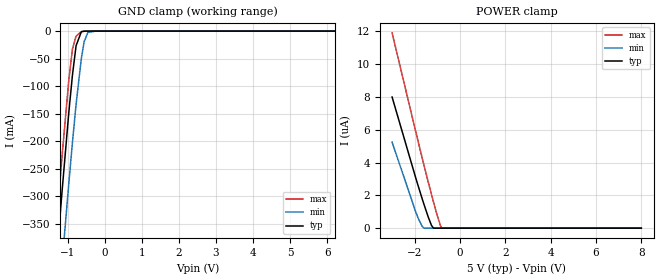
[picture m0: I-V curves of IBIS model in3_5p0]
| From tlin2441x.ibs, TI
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|   in3_5p0 Model
[Model]   in3_5p0
Model_type   Input
Vinl = 0.8
Vinh = 2
|   typ   min   max
C_comp   4.243pF   3.996pF   4.243pF
|  Where Nom  PVT is Nominal Process, 5.0V,   27C
|   Fast PVT is Strong Process,  5.5,   -40C
|   Slow PVT is Weak Process,   4.5V,   150C
[Voltage Range]   5   4.5   5.5
|Junction Temperature
[Temperature Range]   27   150   -40
[Power Clamp Reference]   5   4.5   5.5
[GND Clamp Reference]   0   0   0
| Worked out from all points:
|   GND clamp passes 1 mA (typ) near -0.63 V on its own axis
[GND Clamp]
|   Voltage   I(typ)   I(min)   I(max)
-3V       -1.934A    -2.032A    -1.89A
-1.537V   -616.5mA   -743.5mA   -555.5mA
-1.196V   -324mA     -455.1mA   -260.2mA
-1.152V   -287.7mA   -418.9mA   -223.9mA
-976mV    -149.3mA   -278.1mA   -90.15mA
-877mV    -80.52mA   -203.1mA   -32.85mA
-778mV    -26.6mA    -133.2mA   -9.143mA
-635mV    -1.049mA   -49.26mA   -1.125mA
-558mV    -166.2uA   -18.82mA   -193.4uA
-459mV    -24.47uA   -2.442mA   -25.18uA
-239mV    -12.7uA    -19.14uA   -14.71uA
8V        0A         0A         0A
[POWER Clamp]
|   Voltage   I(typ)   I(min)   I(max)
-3V       7.991uA    5.243uA    11.9uA
-1.955V   3.056uA    983.8nA    5.872uA
-1.834V   2.508uA    561.3nA    5.188uA
-1.669V   1.778uA    101.8nA    4.261uA
-1.581V   1.401uA    0A         3.771uA
-1.405V   679nA      0A         2.813uA
-1.262V   169.8nA    0A         2.059uA
-1.174V   0A         0A         1.602uA
-1.02V    0A         0A         826.8nA
-855mV    0A         0A         113.1nA
-811mV    0A         0A         6.303nA
8V        0A         0A         0A
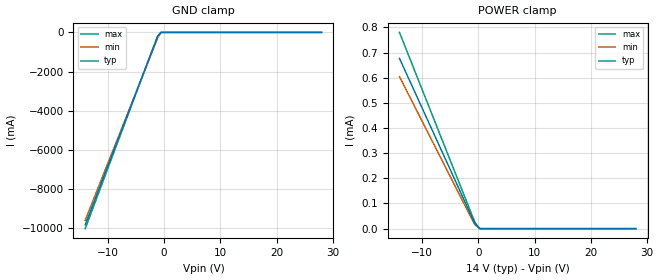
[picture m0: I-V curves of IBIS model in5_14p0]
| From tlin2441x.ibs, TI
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|   in5_14p0 Model
[Model]   in5_14p0
Model_type   Input
Vinl = 11
Vinh = 12
|   typ   min   max
C_comp   5.416pF   5.292pF   5.491pF
|  Where Nom  PVT is Nominal Process, 14.0V,   27C
|   Fast PVT is Strong Process,  16.0,   -40C
|   Slow PVT is Weak Process,   12.0V,   150C
[Model spec]
|subparameter
Vinl   11   9   13
Vinh   12   10   14
[Voltage Range]   14   12   16
|Junction Temperature
[Temperature Range]   27   150   -40
[Power Clamp Reference]   14   12   16
[GND Clamp Reference]   0   0   0
[GND Clamp]
|   Voltage   I(typ)   I(min)   I(max)
-14V      -9.81A     -9.582A    -10.01A
-1.148V   -225.2mA   -296.1mA   -196.2mA
-560mV    -10.69uA   -3.202mA   -8.464uA
238mV     -1.926uA   -161.2uA   -2.474uA
322mV     -1.458uA   -1.139uA   -2.151uA
28V       0A         0A         0A
[POWER Clamp]
|   Voltage   I(typ)   I(min)   I(max)
-14V      676.6uA    604.2uA    779.9uA
-1.148V   46.93uA    38.58uA    55.81uA
-560mV    19.26uA    14.6uA     23.85uA
238mV     897.5nA    673.4nA    1.118uA
322mV     0A         0A         0A
28V       0A         0A         0A
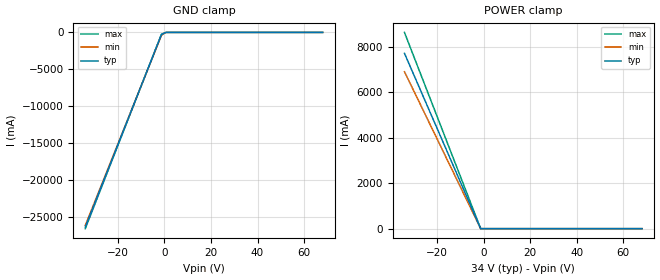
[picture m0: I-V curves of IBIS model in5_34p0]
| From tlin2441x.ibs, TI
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|   in5_34p0 Model
[Model]   in5_34p0
Model_type   Input
Vinl = 31
Vinh = 32
|   typ   min   max
C_comp   3.834pF   3.781pF   3.834pF
|  Where Nom  PVT is Nominal Process, 34.0V,   27C
|   Fast PVT is Strong Process,  36.0,   -40C
|   Slow PVT is Weak Process,   32.0V,   150C
[Model spec]
|subparameter
Vinl   31   29   33
Vinh   32   30   34
[Voltage Range]   34   32   36
[Temperature Range]   27   150   -40
[Power Clamp Reference]   34   32   36
[GND Clamp Reference]   0   0   0
[GND Clamp]
|   Voltage   I(typ)   I(min)   I(max)
-34V      -26.35A    -26.11A    -26.55A
-1.258V   -283.2mA   -377.4mA   -244mA
-238mV    -134.2mA   -178.8mA   -115.6mA
578mV     -14.91mA   -19.87mA   -12.85mA
782mV     -4.405uA   -3.704uA   -5.883uA
68V       0A         0A         0A
[POWER Clamp]
|   Voltage   I(typ)   I(min)   I(max)
-34V      7.726A     6.916A     8.648A
-1.258V   55.12uA    46.31uA    64.83uA
-238mV    26.03uA    21.85uA    30.62uA
578mV     2.746uA    2.289uA    3.247uA
782mV     0A         0A         0A
68V       0A         0A         0A
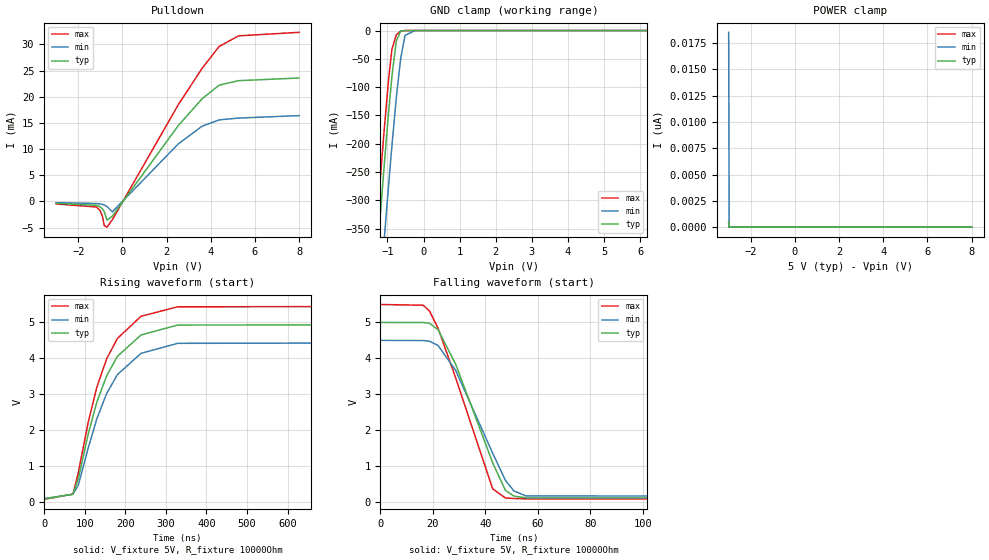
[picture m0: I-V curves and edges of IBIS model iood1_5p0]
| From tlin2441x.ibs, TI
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|   iood1_5p0 Model
[Model]   iood1_5p0
Model_type   I/O_open_drain
Polarity   Non-Inverting
Enable   Active-Low
Vinl = 0.8
Vinh = 2
Vmeas = 2.5
Vref = 5
Cref = 2pF
Rref = 10000
|   typ   min   max
C_comp   4.504pF   4.262pF   4.504pF
|  Where Nom  PVT is Nominal Process, 5.0V,   27C
|   Fast PVT is Strong Process,  5.5,   -40C
|   Slow PVT is Weak Process,   4.5V,   150C
[Voltage Range]   5   4.5   5.5
|Junction Temperature
[Temperature Range]   27   150   -40
[Pullup Reference]   5   4.5   5.5
[Pulldown Reference]   0   0   0
[Power Clamp Reference]   5   4.5   5.5
[GND Clamp Reference]   0   0   0
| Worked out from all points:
|   slope of the pulldown table from 0 to 0.75 V, typ, clamps not added: 165 ohm
|   GND clamp passes 1 mA (typ) near -0.63 V on its own axis
|   falling waveform, V_fixture 5V, R_fixture 10000Ohm: 20-80 % time 15.3ns typ, 16.1ns min, 14.6ns max; typ from 5 V to 0.08 V
|   rising waveform, V_fixture 5V, R_fixture 10000Ohm: 20-80 % time 85.8ns typ, 89ns min, 83.2ns max; typ from 0.08 V to 5 V
[Pulldown]
|   Voltage   I(typ)   I(min)   I(max)
-3V       -362.7uA   -227.6uA   -475.8uA
-1.185V   -734.4uA   -383.9uA   -1.054mA
-1.009V   -1.022mA   -473uA     -1.717mA
-899mV    -1.428mA   -567.9uA   -2.915mA
-822mV    -1.969mA   -670.4uA   -4.619mA
-701mV    -3.562mA   -943.5uA   -4.905mA
-459mV    -2.81mA    -1.979mA   -3.509mA
2.533V    14.51mA    11mA       18.49mA
3.611V    19.62mA    14.38mA    25.43mA
4.381V    22.21mA    15.57mA    29.59mA
5.261V    23.06mA    15.92mA    31.62mA
8V        23.57mA    16.39mA    32.29mA
[GND Clamp]
|   Voltage   I(typ)   I(min)   I(max)
-3V       -1.935A    -2.032A    -1.89A
-1.537V   -616.6mA   -743.7mA   -555.7mA
-1.207V   -333.3mA   -464.4mA   -269.5mA
-1.141V   -278.9mA   -410.2mA   -215.2mA
-1.086V   -234.5mA   -365.5mA   -171.4mA
-965mV    -141.4mA   -269.8mA   -83.06mA
-877mV    -80.75mA   -203.3mA   -33.19mA
-756mV    -18.43mA   -119mA     -7.406mA
-635mV    -1.092mA   -49.56mA   -1.17mA
-514mV    -52.22uA   -8.686mA   -55.92uA
-239mV    0A         -7.41uA    0A
8V        0A         0A         0A
[POWER Clamp]
|   Voltage   I(typ)   I(min)   I(max)
-3V       445.5pA    18.51nA    459.1pA
-2.978V   0A         0A         0A
-2.967V   0A         0A         0A
8V        0A         0A         0A
[Ramp]
R_load = 10000
|   typ   min   max
dV/dt_r   2.9519/8.54854e-08   2.6451/8.86345e-08   3.25753/8.27986e-08
dV/dt_f   2.9519/1.52343e-08   2.6451/1.60653e-08   3.25753/1.46163e-08
[Falling Waveform]
V_fixture = 5V
V_fixture_min = 4.5V
V_fixture_max = 5.5V
R_fixture = 10000Ohm
C_fixture = 0F
|   Time   V(typ)   V(min)   V(max)
0s        5V         4.5V       5.5V
16.33ns   4.998V     4.496V     5.48V
18.68ns   4.978V     4.479V     5.323V
22ns      4.797V     4.358V     4.838V
28.7ns    3.835V     3.663V     3.455V
42.81ns   1.083V     1.35V      362.2mV
47.62ns   320.3mV    600mV      108.5mV
50.85ns   161.9mV    305.4mV    93.44mV
55.48ns   111mV      164.9mV    85.05mV
5us       80.16mV    91.37mV    70.78mV
[Rising Waveform]
V_fixture = 5V
V_fixture_min = 4.5V
V_fixture_max = 5.5V
R_fixture = 10000Ohm
C_fixture = 0F
|   Time   V(typ)   V(min)   V(max)
0s        80.16mV    91.37mV    70.78mV
71.29ns   214.9mV    213.3mV    215.2mV
84.38ns   644.2mV    465.9mV    818.2mV
109ns     1.899V     1.509V     2.229V
130ns     2.778V     2.316V     3.196V
154.4ns   3.518V     3.024V     3.991V
180.8ns   4.056V     3.548V     4.556V
238.8ns   4.651V     4.139V     5.171V
329ns     4.927V     4.418V     5.436V
5us       5V         4.5V       5.5V
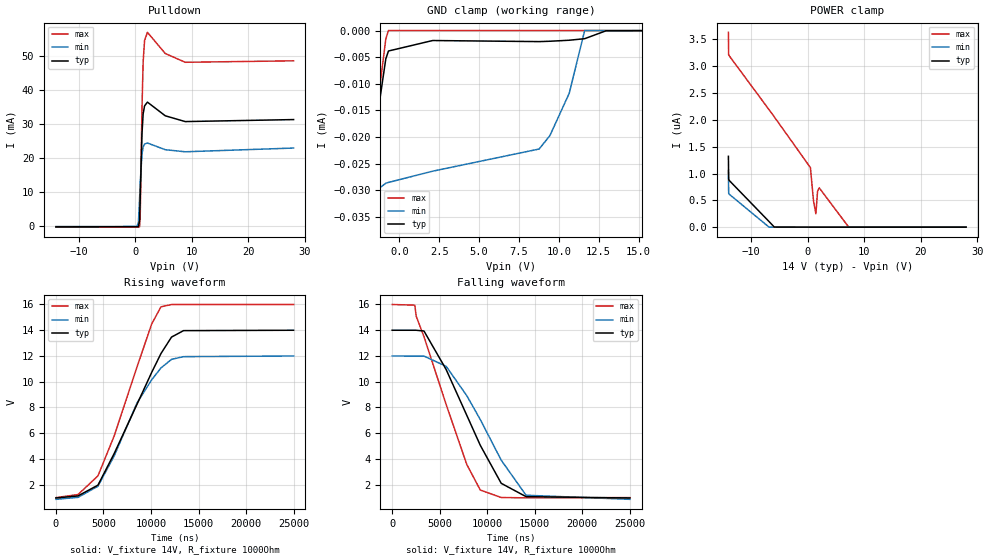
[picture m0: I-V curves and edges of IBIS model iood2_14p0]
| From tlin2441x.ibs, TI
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|   iood2_14p0 Model
[Model]   iood2_14p0
Model_type   I/O_open_drain
Polarity   Non-Inverting
Enable   Active-Low
Vinl = 2.8
Vinh = 11.9
Vmeas = 7
Vref = 14
Cref = 2pF
Rref = 1000
|   typ   min   max
C_comp   6.786pF   6.632pF   7.441pF
|  Where Nom  PVT is Nominal Process, 14.0V,   27C
|   Fast PVT is Strong Process,  16.0,   -40C
|   Slow PVT is Weak Process,   12.0V,   150C
[Model spec]
|subparameter
Vinl   2.8   2.4   3.2
Vinh   11.9   10.2   13.6
[Voltage Range]   14   12   16
|Junction Temperature
[Temperature Range]   27   150   -40
[Pullup Reference]   14   12   16
[Pulldown Reference]   0   -0   -0
[Power Clamp Reference]   14   12   16
[GND Clamp Reference]   0   0   0
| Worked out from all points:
|   slope of the pulldown table from 0 to 2.1 V, typ, clamps not added: 57.3 ohm
|   falling waveform, V_fixture 14V, R_fixture 1000Ohm: 20-80 % time 4.85us typ, 4.91us min, 4.05us max; typ from 14 V to 0.969 V
|   rising waveform, V_fixture 14V, R_fixture 1000Ohm: 20-80 % time 4.86us typ, 4.31us min, 4.14us max; typ from 0.969 V to 14 V
[Pulldown]
|   Voltage   I(typ)   I(min)   I(max)
-14V      -300.5uA   -219.8uA   -400.2uA
280mV     -279.7uA   -183.1uA   -374.2uA
574mV     -270.7uA   786.7uA    -366.6uA
784mV     1.521mA    8.053mA    -303.7uA
910mV     9.268mA    13.07mA    4.138mA
1.204V    26.99mA    21.05mA    34.35mA
1.414V    33.01mA    23.23mA    48.29mA
1.666V    35.35mA    24.1mA     54.65mA
2.17V     36.45mA    24.41mA    57.03mA
5.32V     32.43mA    22.43mA    50.79mA
8.848V    30.72mA    21.82mA    48.2mA
28V       31.31mA    22.92mA    48.63mA
[GND Clamp]
|   Voltage   I(typ)   I(min)   I(max)
-14V      -297.2uA   -267.5uA   -336.2uA
-2.324V   -36.2uA    -37.33uA   -37.54uA
-1.736V   -23.33uA   -30.73uA   -22.73uA
-854mV    -5.32uA    -28.65uA   -1.576uA
-686mV    -3.845uA   -28.51uA   0A
2.086V    -1.877uA   -26.4uA    0A
8.764V    -2.081uA   -22.24uA   0A
9.436V    -2.014uA   -19.74uA   0A
10.65V    -1.824uA   -11.8uA    0A
11.62V    -1.534uA   0A         0A
12.96V    -50.39nA   0A         0A
28V       0A         0A         0A
[POWER Clamp]
|   Voltage   I(typ)   I(min)   I(max)
-14V      1.321uA    1.061uA    3.633uA
-13.96V   891.5nA    635nA      3.217uA
-13.79V   863.5nA    608.2nA    3.186uA
-6.818V   104.6nA    120.1pA    2.19uA
-5.894V   1.97nA     0A         2.057uA
490mV     0A         0A         1.11uA
1.036V    0A         0A         489.3nA
1.456V    0A         0A         249.6nA
1.75V     0A         0A         668.6nA
2.044V    0A         0A         733.5nA
7.252V    0A         0A         1.455nA
28V       0A         0A         0A
[Ramp]
R_load = 1000
|   typ   min   max
dV/dt_r   7.8177/4.84794e-06   6.67991/4.29211e-06   8.99927/4.1215e-06
dV/dt_f   7.8177/4.85367e-06   6.67991/4.8993e-06   8.99927/4.04204e-06
[Falling Waveform]
V_fixture = 14V
V_fixture_min = 12V
V_fixture_max = 16V
R_fixture = 1000Ohm
C_fixture = 0F
|   Time   V(typ)   V(min)   V(max)
0s        14V        12V        16V
2.38us    14V        11.99V     15.95V
2.528us   14V        11.99V     15.09V
3.347us   13.94V     11.99V     13.5V
5.677us   10.95V     11.2V      8.239V
7.85us    7.39V      8.916V     3.572V
9.267us   5.066V     7.064V     1.59V
11.47us   2.11V      3.909V     1.007V
14.08us   1.075V     1.185V     981.8mV
25us      969.3mV    866.6mV    999.4mV
[Rising Waveform]
V_fixture = 14V
V_fixture_min = 12V
V_fixture_max = 16V
R_fixture = 1000Ohm
C_fixture = 0F
|   Time   V(typ)   V(min)   V(max)
0s        969.3mV    866.6mV    999.4mV
2.324us   1.132V     1.021V     1.237V
4.421us   1.968V     1.885V     2.687V
6.121us   4.41V      4.228V     5.775V
8.544us   8.271V     8.37V      11.18V
10.07us   10.72V     10.15V     14.48V
11.05us   12.19V     11.07V     15.82V
12.16us   13.47V     11.74V     16V
13.42us   13.97V     11.95V     16V
25us      14V        12V        16V
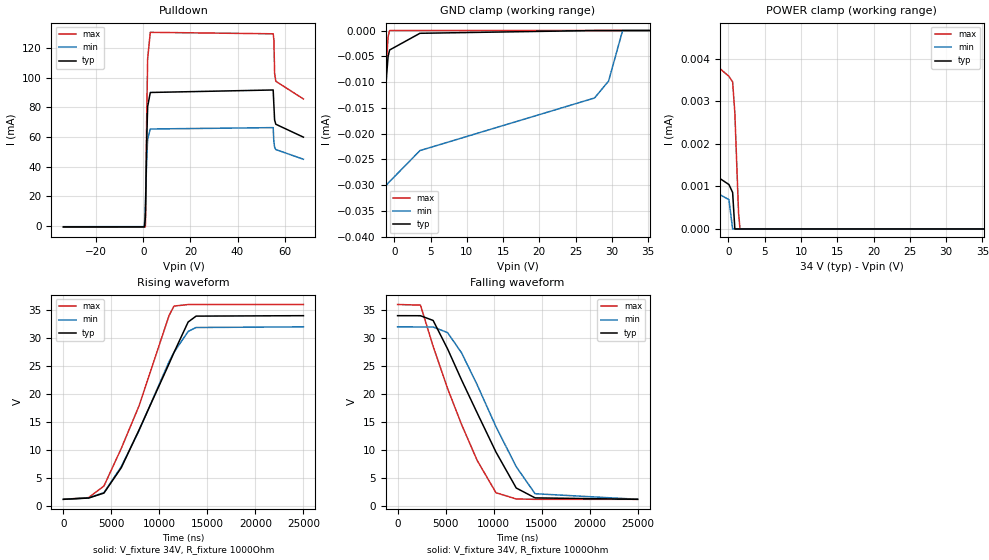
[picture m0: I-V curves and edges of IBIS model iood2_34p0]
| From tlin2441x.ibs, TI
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|   iood2_34p0 Model
[Model]   iood2_34p0
Model_type   I/O_open_drain
Polarity   Non-Inverting
Enable   Active-Low
Vinl = 6.8
Vinh = 28.9
Vmeas = 17
Vref = 34
Cref = 2pF
Rref = 1000
|   typ   min   max
C_comp   5.803pF   5.723pF   6.161pF
|  Where Nom  PVT is Nominal Process, 34.0V,   27C
|   Fast PVT is Strong Process,  36.0,   -40C
|   Slow PVT is Weak Process,   32.0V,   150C
[Model spec]
|subparameter
Vinl   6.8   6.4   7.2
Vinh   28.9   27.2   30.6
[Voltage Range]   34   32   36
|Junction Temperature
[Temperature Range]   27   150   -40
[Pullup Reference]   34   32   36
[Pulldown Reference]   0   -0   -0
[Power Clamp Reference]   34   32   36
[GND Clamp Reference]   0   0   0
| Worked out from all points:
|   slope of the pulldown table from 0 to 5.1 V, typ, clamps not added: 56.8 ohm
|   POWER clamp passes 1 mA (typ) near -21.23 V on its own axis
|   falling waveform, V_fixture 34V, R_fixture 1000Ohm: 20-80 % time 5.43us typ, 5.09us min, 4.67us max; typ from 34 V to 1.12 V
|   rising waveform, V_fixture 34V, R_fixture 1000Ohm: 20-80 % time 5.23us typ, 4.89us min, 4.65us max; typ from 1.12 V to 34 V
[Pulldown]
|   Voltage   I(typ)   I(min)   I(max)
-34V      -731.9uA   -590.3uA   -901.2uA
374mV     -715.2uA   -552.4uA   -876.9uA
782mV     4.155mA    10.28mA    -811.9uA
884mV     8.931mA    16.62mA    1.897mA
1.394V    57.12mA    44.58mA    72.35mA
1.802V    80.53mA    58.57mA    112.9mA
2.924V    90.07mA    65.4mA     130.7mA
55.15V    91.76mA    66.33mA    129.7mA
55.45V    81.51mA    56.53mA    125.7mA
55.76V    71.46mA    53.19mA    103.1mA
56.27V    68.61mA    51.51mA    97.64mA
68V       59.89mA    44.96mA    85.69mA
[GND Clamp]
|   Voltage   I(typ)   I(min)   I(max)
-34V      -746.5uA   -667uA     -852.3uA
-2.482V   -39.43uA   -39.89uA   -41.28uA
-2.38V    -37.18uA   -38.11uA   -38.7uA
-1.972V   -28.21uA   -32.86uA   -28.39uA
-1.054V   -8.644uA   -29.94uA   -5.684uA
-850mV    -5.027uA   -29.61uA   -1.204uA
-646mV    -3.779uA   -29.31uA   0A
3.536V    -537.8nA   -23.29uA   0A
27.61V    0A         -13.09uA   0A
29.55V    0A         -9.798uA   0A
31.48V    0A         0A         0A
68V       0A         0A         0A
[POWER Clamp]
|   Voltage   I(typ)   I(min)   I(max)
-34V      3.941A     3.346A     4.578A
-21.05V   32.09uA    64.38uA    375.6mA
-20.23V   3.232uA    7.134uA    167.3mA
-19.62V   3.168uA    2.974uA    26.5mA
-19.21V   3.127uA    2.522uA    117.3uA
-8.398V   2.001uA    1.48uA     4.82uA
68mV      1.044uA    688.9nA    3.587uA
578mV     857.8nA    0A         3.457uA
884mV     0A         0A         2.724uA
1.394V    0A         0A         376.6nA
1.598V    0A         0A         0A
68V       0A         0A         0A
[Ramp]
R_load = 1000
|   typ   min   max
dV/dt_r   19.7248/5.22925e-06   18.5236/4.88249e-06   20.9252/4.65492e-06
dV/dt_f   19.7248/5.43378e-06   18.5236/5.08419e-06   20.9252/4.67566e-06
[Falling Waveform]
V_fixture = 34V
V_fixture_min = 32V
V_fixture_max = 36V
R_fixture = 1000Ohm
C_fixture = 0F
|   Time   V(typ)   V(min)   V(max)
0s        34V        32V        36V
2.383us   33.99V     31.98V     35.89V
3.705us   33.14V     31.97V     28.51V
5.205us   28.07V     30.97V     20.98V
6.658us   22.52V     27.37V     14.55V
8.296us   16.57V     21.61V     8.071V
10.25us   9.579V     14.12V     2.302V
12.36us   3.146V     6.963V     1.184V
14.32us   1.381V     2.126V     1.121V
25us      1.122V     1.126V     1.12V
[Rising Waveform]
V_fixture = 34V
V_fixture_min = 32V
V_fixture_max = 36V
R_fixture = 1000Ohm
C_fixture = 0F
|   Time   V(typ)   V(min)   V(max)
0s        1.122V     1.126V     1.12V
2.623us   1.351V     1.373V     1.426V
4.222us   2.24V      2.32V      3.501V
6.028us   6.78V      6.962V     10.24V
7.88us    13.55V     13.43V     17.86V
11us      25.37V     25.74V     34V
11.52us   27.42V     27.44V     35.72V
12.99us   32.86V     31.17V     35.99V
13.82us   33.92V     31.88V     35.99V
25us      34V        32V        36V
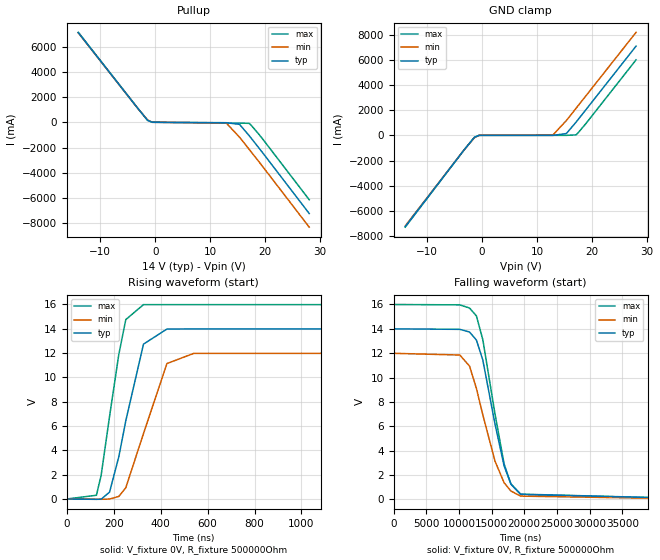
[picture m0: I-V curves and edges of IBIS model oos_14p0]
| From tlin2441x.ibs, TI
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|   oos_14p0 Model
[Model]   oos_14p0
Model_type   Open_source
Polarity   Non-Inverting
Vmeas = 7
Vref = 0
Cref = 2pF
Rref = 500000
|   typ   min   max
C_comp   1.013pF   0.976pF   1.013pF
|  Where Nom  PVT is Nominal Process, 14.0V,   27C
|   Fast PVT is Strong Process,  16.0,   -40C
|   Slow PVT is Weak Process,   12.0V,   150C
[Voltage Range]   14   12   16
|Junction Temperature
[Temperature Range]   27   150   -40
[Pullup Reference]   14   12   16
[Pulldown Reference]   0   0   0
[Power Clamp Reference]   14   12   16
[GND Clamp Reference]   0   0   0
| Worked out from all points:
|   slope of the pullup table from 0 to 2.1 V, typ, clamps not added: 142 ohm
|   falling waveform, V_fixture 0V, R_fixture 500000Ohm: 20-80 % time 3.14us typ, 3.55us min, 3.03us max; typ from 14 V to 0 V
|   rising waveform, V_fixture 0V, R_fixture 500000Ohm: 20-80 % time 89.4ns typ, 110ns min, 73.5ns max; typ from 0 V to 14 V
[GND Clamp]
|   Voltage   I(typ)   I(min)   I(max)
-14V      -7.247A    -7.195A    -7.29A
-3.5V     -1.275A    -1.274A    -1.28A
-3.08V    -1.045A    -1.045A    -1.048A
-1.4V     -157.1mA   -187mA     -145.4mA
-560mV    -1.434uA   -250.3uA   -1.025uA
12.88V    1.327nA    33.61mA    1.167nA
15.32V    142.8mA    1.178A     1.63nA
17.08V    1.048A     2.147A     37.06mA
17.5V     1.279A     2.379A     226.5mA
18.89V    2.045A     3.145A     944.9mA
19.6V     2.44A      3.541A     1.339A
28V       7.089A     8.181A     5.998A
[Pullup]
|   Voltage   I(typ)   I(min)   I(max)
-14V      7.117A     7.096A     7.143A
-3.5V     1.285A     1.281A     1.294A
-3.08V    1.053A     1.051A     1.061A
-1.4V     163.7mA    191.7mA    154.9mA
-560mV    4.279mA    2.278mA    7.702mA
12.88V    -30.79mA   -40.71mA   -59.53mA
15.32V    -161.6mA   -1.179A    -59.53mA
17.08V    -1.059A    -2.145A    -80.65mA
17.5V     -1.289A    -2.377A    -261.2mA
18.8V     -2.007A    -3.097A    -922.5mA
19.6V     -2.454A    -3.547A    -1.362A
28V       -7.237A    -8.32A     -6.141A
[Ramp]
R_load = 500000
|   typ   min   max
dV/dt_r   8.39773/8.94312e-08   7.19586/1.10056e-07   9.59854/7.35254e-08
dV/dt_f   8.39773/3.13035e-06   7.19586/3.55426e-06   9.59854/3.02909e-06
[Falling Waveform]
V_fixture = 0V
V_fixture_min = 0V
V_fixture_max = 0V
R_fixture = 500000Ohm
C_fixture = 0F
|   Time   V(typ)   V(min)   V(max)
0s        14V        11.99V     16V
10.13us   13.96V     11.85V     15.97V
11.62us   13.74V     10.94V     15.71V
12.67us   13.08V     9.105V     15.06V
13.65us   11.44V     6.937V     13.11V
15.51us   6.198V     3.143V     7.032V
16.91us   2.74V      1.359V     2.903V
17.95us   1.266V     684.2mV    1.247V
19.44us   426.4mV    264.5mV    401.2mV
50us      70.4uV     248.3uV    69.07uV
[Rising Waveform]
V_fixture = 0V
V_fixture_min = 0V
V_fixture_max = 0V
R_fixture = 500000Ohm
C_fixture = 0F
|   Time   V(typ)   V(min)   V(max)
0s        70.4uV     248.3uV    69.08uV
126.3ns   -28.06mV   -19.34mV   306.2mV
146.5ns   -16.63mV   -22.46mV   1.954V
182.3ns   564.5mV    -6.325mV   6.796V
221.6ns   3.464V     209.4mV    11.88V
251.5ns   6.433V     930.9mV    14.76V
326.9ns   12.74V     5.383V     15.99V
426.6ns   13.98V     11.14V     15.99V
541.1ns   13.99V     11.98V     15.99V
50us      14V        11.99V     16V
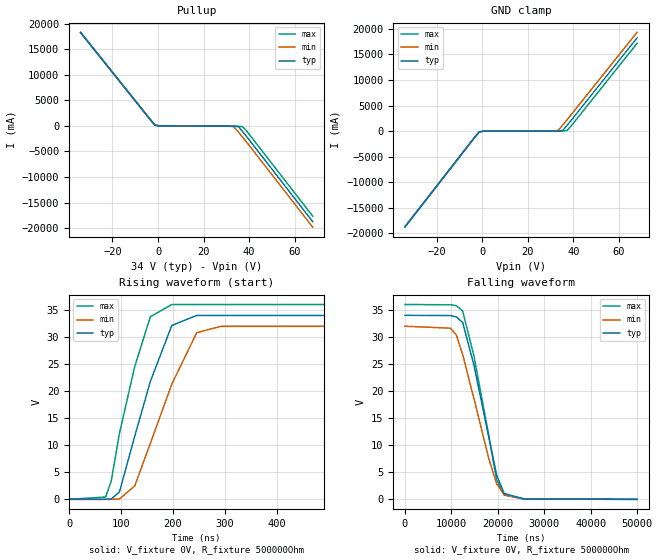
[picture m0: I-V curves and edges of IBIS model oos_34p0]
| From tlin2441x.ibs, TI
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|   oos_34p0 Model
[Model]   oos_34p0
Model_type   Open_source
Polarity   Non-Inverting
Vmeas = 17
Vref = 0
Cref = 2pF
Rref = 500000
|   typ   min   max
C_comp   0.698pF   0.616pF   0.701pF
|  Where Nom  PVT is Nominal Process, 34.0V,   27C
|   Fast PVT is Strong Process,  36.0,   -40C
|   Slow PVT is Weak Process,   32.0V,   150C
[Voltage Range]   34   32   36
|Junction Temperature
[Temperature Range]   27   150   -40
[Pullup Reference]   34   32   36
[Pulldown Reference]   0   0   0
[Power Clamp Reference]   34   32   36
[GND Clamp Reference]   0   0   0
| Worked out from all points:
|   slope of the pullup table from 0 to 5.1 V, typ, clamps not added: 66.1 ohm
|   falling waveform, V_fixture 0V, R_fixture 500000Ohm: 20-80 % time 4.94us typ, 5.63us min, 4.67us max; typ from 34 V to 0 V
|   rising waveform, V_fixture 0V, R_fixture 500000Ohm: 20-80 % time 61.6ns typ, 73.9ns min, 50.7ns max; typ from 0 V to 34 V
[GND Clamp]
|   Voltage   I(typ)   I(min)   I(max)
-34V      -18.72A    -18.65A    -18.78A
-3.4V     -1.22A     -1.219A    -1.225A
-2.788V   -896.7mA   -905.6mA   -895.9mA
-1.36V    -141.9mA   -173.1mA   -128.2mA
680mV     -2.591nA   -2.248nA   -2.751nA
31.28V    3.223nA    3.566nA    3.063nA
33.32V    3.611nA    162mA      3.451nA
35.36V    143.6mA    1.202A     3.838nA
37.2V     1.116A     2.212A     132mA
38.73V    1.957A     3.058A     864.3mA
39.44V    2.352A     3.452A     1.251A
68V       18.25A     19.33A     17.18A
[Pullup]
|   Voltage   I(typ)   I(min)   I(max)
-34V      18.26A     18.22A     18.3A
-3.4V     1.23A      1.227A     1.238A
-2.788V   905.3mA    912.1mA    908.3mA
-1.36V    148.8mA    178.1mA    138.5mA
680mV     -5.096mA   -2.482mA   -9.119mA
31.28V    -35mA      -13.3mA    -64.27mA
33.32V    -35mA      -168.6mA   -64.27mA
35.36V    -164.4mA   -1.204A    -64.27mA
37.2V     -1.129A    -2.211A    -171mA
38.73V    -1.97A     -3.061A    -893.2mA
39.44V    -2.365A    -3.458A    -1.276A
68V       -18.74A    -19.8A     -17.66A
[Ramp]
R_load = 500000
|   typ   min   max
dV/dt_r   20.3946/6.15901e-08   19.1895/7.39057e-08   21.5967/5.07121e-08
dV/dt_f   20.3946/4.93939e-06   19.1895/5.63048e-06   21.5967/4.66086e-06
[Falling Waveform]
V_fixture = 0V
V_fixture_min = 0V
V_fixture_max = 0V
R_fixture = 500000Ohm
C_fixture = 0F
|   Time   V(typ)   V(min)   V(max)
0s        33.99V     31.98V     35.99V
9.799us   33.95V     31.61V     35.94V
11.07us   33.7V      30.36V     35.77V
12.43us   32.66V     26.72V     34.79V
14.84us   24.83V     18.65V     26.53V
18.07us   11.42V     7.514V     11.71V
19.73us   4.545V     2.918V     3.642V
21.36us   1.09V      842.7mV    797mV
25.74us   49.55mV    55.79mV    44.28mV
50us      153.7uV    335.9uV    149.9uV
[Rising Waveform]
V_fixture = 0V
V_fixture_min = 0V
V_fixture_max = 0V
R_fixture = 500000Ohm
C_fixture = 0F
|   Time   V(typ)   V(min)   V(max)
0s        153.7uV    335.5uV    149.9uV
70.33ns   6.022mV    1.596mV    424.3mV
81.14ns   61.18mV    1.79mV     3.362V
96.95ns   1.354V     63.91mV    12.19V
126.3ns   11.65V     2.467V     24.52V
156.4ns   21.79V     10.34V     33.73V
197.6ns   32.11V     21.26V     35.98V
245.5ns   33.97V     30.78V     35.98V
292ns     33.97V     31.96V     35.98V
50us      33.99V     31.98V     35.99V
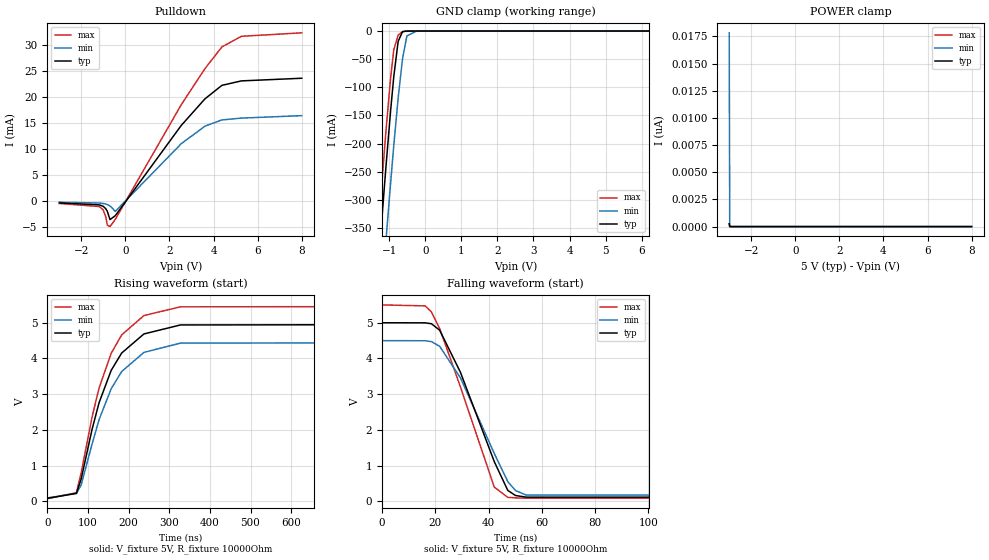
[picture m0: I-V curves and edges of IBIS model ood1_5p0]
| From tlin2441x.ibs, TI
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|   ood1_5p0 Model
[Model]   ood1_5p0
Model_type   Open_drain
Polarity   Non-Inverting
Vmeas = 2.5
Vref = 5
Cref = 2pF
Rref = 10000
|   typ   min   max
C_comp   4.484pF   4.223pF   4.484pF
|  Where Nom  PVT is Nominal Process, 5.0V,   27C
|   Fast PVT is Strong Process,  5.5,   -40C
|   Slow PVT is Weak Process,   4.5V,   150C
[Voltage Range]   5   4.5   5.5
|Junction Temperature
[Temperature Range]   27   150   -40
[Pullup Reference]   5   4.5   5.5
[Pulldown Reference]   0   0   0
[Power Clamp Reference]   5   4.5   5.5
[GND Clamp Reference]   0   0   0
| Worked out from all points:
|   slope of the pulldown table from 0 to 0.75 V, typ, clamps not added: 165 ohm
|   GND clamp passes 1 mA (typ) near -0.63 V on its own axis
|   falling waveform, V_fixture 5V, R_fixture 10000Ohm: 20-80 % time 15.2ns typ, 16ns min, 14.6ns max; typ from 5 V to 0.08 V
|   rising waveform, V_fixture 5V, R_fixture 10000Ohm: 20-80 % time 82.7ns typ, 85.9ns min, 79.8ns max; typ from 0.08 V to 5 V
[Pulldown]
|   Voltage   I(typ)   I(min)   I(max)
-3V       -362.7uA   -227.6uA   -475.8uA
-1.185V   -734.3uA   -383.9uA   -1.054mA
-1.009V   -1.022mA   -473uA     -1.716mA
-899mV    -1.428mA   -567.8uA   -2.915mA
-822mV    -1.969mA   -670.3uA   -4.619mA
-701mV    -3.562mA   -943.4uA   -4.907mA
-459mV    -2.81mA    -1.979mA   -3.509mA
2.533V    14.51mA    11mA       18.49mA
3.611V    19.62mA    14.38mA    25.43mA
4.381V    22.21mA    15.57mA    29.59mA
5.261V    23.06mA    15.92mA    31.62mA
8V        23.57mA    16.39mA    32.29mA
[GND Clamp]
|   Voltage   I(typ)   I(min)   I(max)
-3V       -1.934A    -2.032A    -1.89A
-1.537V   -616.6mA   -743.7mA   -555.6mA
-1.207V   -333.3mA   -464.4mA   -269.5mA
-1.141V   -278.9mA   -410.1mA   -215.2mA
-1.086V   -234.5mA   -365.5mA   -171.4mA
-965mV    -141.4mA   -269.8mA   -83.03mA
-877mV    -80.73mA   -203.3mA   -33.15mA
-756mV    -18.4mA    -119mA     -7.369mA
-635mV    -1.081mA   -49.53mA   -1.159mA
-514mV    -51.31uA   -8.66mA    -54.95uA
-239mV    0A         -7.254uA   0A
8V        0A         0A         0A
[POWER Clamp]
|   Voltage   I(typ)   I(min)   I(max)
-3V       257.3pA    17.83nA    255.6pA
-2.978V   0A         0A         0A
-2.967V   0A         0A         0A
8V        0A         0A         0A
[Ramp]
R_load = 10000
|   typ   min   max
dV/dt_r   2.9519/8.24603e-08   2.64511/8.57168e-08   3.25753/7.97977e-08
dV/dt_f   2.9519/1.51908e-08   2.64511/1.60177e-08   3.25753/1.45863e-08
[Falling Waveform]
V_fixture = 5V
V_fixture_min = 4.5V
V_fixture_max = 5.5V
R_fixture = 10000Ohm
C_fixture = 0F
|   Time   V(typ)   V(min)   V(max)
0s        5V         4.5V       5.5V
16.19ns   4.998V     4.496V     5.473V
18.53ns   4.972V     4.471V     5.302V
21.6ns    4.793V     4.341V     4.843V
29.42ns   3.612V     3.457V     3.201V
42.13ns   1.11V      1.339V     395.8mV
47.2ns    304.3mV    550.7mV    108.5mV
50.1ns    160.1mV    300mV      94.36mV
54.11ns   114.2mV    172.2mV    86.18mV
5us       80.16mV    91.37mV    70.78mV
[Rising Waveform]
V_fixture = 5V
V_fixture_min = 4.5V
V_fixture_max = 5.5V
R_fixture = 10000Ohm
C_fixture = 0F
|   Time   V(typ)   V(min)   V(max)
0s        80.16mV    91.37mV    70.78mV
71.89ns   219.9mV    219.1mV    239.3mV
83.54ns   623.7mV    457mV      797.4mV
110.4ns   2.018V     1.605V     2.364V
127.7ns   2.766V     2.291V     3.177V
157.4ns   3.668V     3.153V     4.145V
183.1ns   4.152V     3.633V     4.66V
237.8ns   4.687V     4.17V      5.202V
327.8ns   4.939V     4.43V      5.447V
5us       5V         4.5V       5.5V
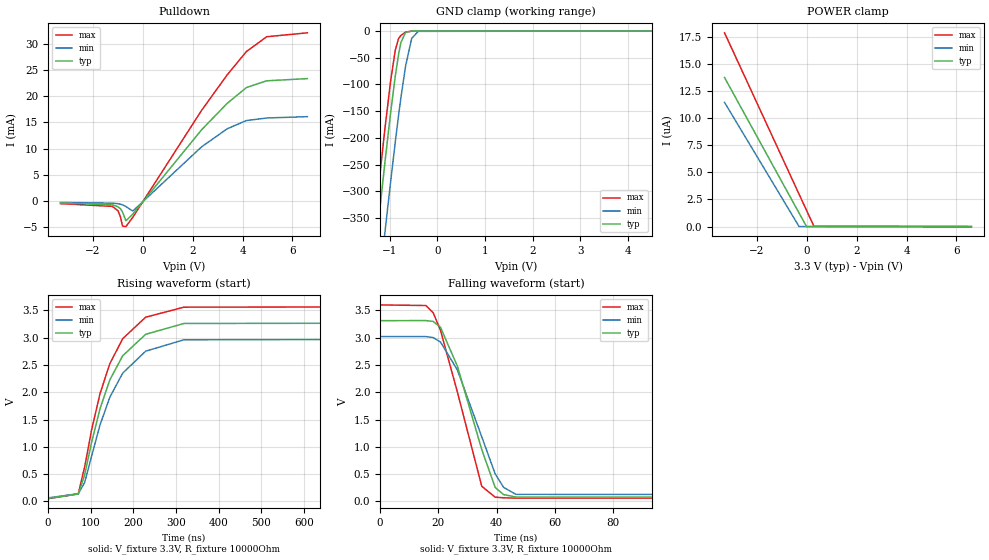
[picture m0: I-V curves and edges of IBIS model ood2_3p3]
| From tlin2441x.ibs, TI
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|   ood2_3p3 Model
[Model]   ood2_3p3
Model_type   Open_drain
Polarity   Non-Inverting
Vmeas = 1.65
Vref = 3.3
Cref = 2pF
Rref = 10000
|   typ   min   max
C_comp   5.292pF   5.008pF   5.317pF
|  Where Nom  PVT is Nominal Process, 3.3V,   27C
|   Fast PVT is Strong Process,  3.6,   -40C
|   Slow PVT is Weak Process,   3.0V,   150C
[Voltage Range]   3.3   3   3.6
|Junction Temperature
[Temperature Range]   27   150   -40
[Pullup Reference]   3.3   3   3.6
[Pulldown Reference]   0   0   0
[Power Clamp Reference]   3.3   3   3.6
[GND Clamp Reference]   0   0   0
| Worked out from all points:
|   slope of the pulldown table from 0 to 0.495 V, typ, clamps not added: 164 ohm
|   GND clamp passes 1 mA (typ) near -0.63 V on its own axis
|   falling waveform, V_fixture 3.3V, R_fixture 10000Ohm: 20-80 % time 10.9ns typ, 12ns min, 10.1ns max; typ from 3.31 V to 0.055 V
|   rising waveform, V_fixture 3.3V, R_fixture 10000Ohm: 20-80 % time 82.8ns typ, 86.3ns min, 79.2ns max; typ from 0.055 V to 3.31 V
[Pulldown]
|   Voltage   I(typ)   I(min)   I(max)
-3.3V     -352.8uA   -232.8uA   -465.8uA
-1.221V   -699.4uA   -370.9uA   -986.1uA
-993.3mV  -1.064mA   -484uA     -1.824mA
-894.3mV  -1.453mA   -573uA     -3.003mA
-815.1mV  -2.036mA   -681.6uA   -4.722mA
-676.5mV  -3.722mA   -1.023mA   -4.836mA
-399.3mV  -2.447mA   -1.872mA   -3.056mA
2.353V    13.57mA    10.33mA    17.26mA
3.382V    18.62mA    13.78mA    24.04mA
4.155V    21.63mA    15.36mA    28.49mA
4.966V    22.92mA    15.84mA    31.31mA
6.6V      23.34mA    16.1mA     32.06mA
[GND Clamp]
|   Voltage   I(typ)   I(min)   I(max)
-3.3V     -2.208A    -2.295A    -2.167A
-1.33V    -437.1mA   -567.1mA   -374mA
-1.231V   -353.3mA   -484.2mA   -289.5mA
-1.102V   -247.4mA   -378.6mA   -184.1mA
-983.4mV  -155mA     -284.1mA   -95.44mA
-884.4mV  -85.5mA    -208.8mA   -36.5mA
-815.1mV  -44.45mA   -158.9mA   -14.41mA
-765.6mV  -21.86mA   -125.3mA   -8.221mA
-666.6mV  -2.38mA    -65.63mA   -2.136mA
-537.9mV  -111.7uA   -13.63mA   -127.2uA
-399.3mV  -17.26uA   -562.7uA   -19.42uA
6.6V      0A         0A         0A
[POWER Clamp]
|   Voltage   I(typ)   I(min)   I(max)
-3.3V     13.74uA    11.45uA    17.86uA
-310.2mV  1.246uA    2.719nA    2.983uA
-13.2mV   8.121nA    0A         1.509uA
283.8mV   0A         0A         34.83nA
6.6V      0A         0A         0A
[Ramp]
R_load = 10000
|   typ   min   max
dV/dt_r   1.95406/8.25313e-08   1.77428/8.60638e-08   2.13086/7.89335e-08
dV/dt_f   1.95406/1.08525e-08   1.77428/1.19582e-08   2.13086/1.00561e-08
[Falling Waveform]
V_fixture = 3.3V
V_fixture_min = 3V
V_fixture_max = 3.6V
R_fixture = 10000Ohm
C_fixture = 0F
|   Time   V(typ)   V(min)   V(max)
0s        3.312V     3.021V     3.6V
15.73ns   3.313V     3.02V      3.589V
18.21ns   3.297V     3.001V     3.457V
20.7ns    3.19V      2.921V     3.136V
26.5ns    2.479V     2.409V     2.006V
34.88ns   949.1mV    1.182V     276.5mV
39.48ns   255.9mV    504.7mV    76.31mV
42.37ns   124mV      256.7mV    64.99mV
46.62ns   79.25mV    127.6mV    58.95mV
5us       55.23mV    63.56mV    48.56mV
[Rising Waveform]
V_fixture = 3.3V
V_fixture_min = 3V
V_fixture_max = 3.6V
R_fixture = 10000Ohm
C_fixture = 0F
|   Time   V(typ)   V(min)   V(max)
0s        55.23mV    63.56mV    48.56mV
70.72ns   134.5mV    140.4mV    137.8mV
85.76ns   488.3mV    345.5mV    632.3mV
101.9ns   1.08V      825.3mV    1.305V
121.8ns   1.7V       1.401V     1.974V
144.9ns   2.227V     1.909V     2.525V
175ns     2.668V     2.35V      2.981V
228.9ns   3.061V     2.752V     3.375V
318.8ns   3.26V      2.961V     3.559V
5us       3.312V     3.021V     3.6V
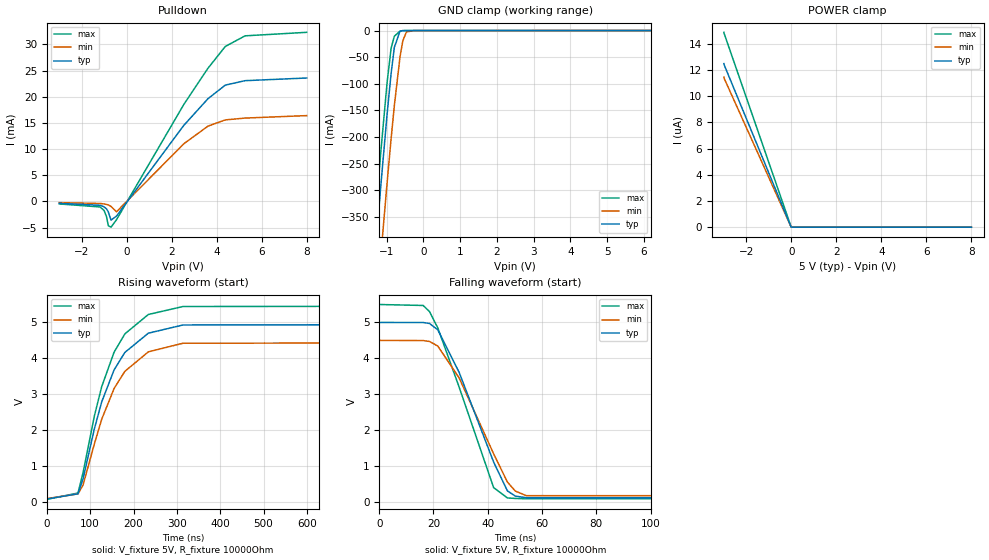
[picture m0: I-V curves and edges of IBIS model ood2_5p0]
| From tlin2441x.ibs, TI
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|   ood2_5p0 Model
[Model]   ood2_5p0
Model_type   Open_drain
Polarity   Non-Inverting
Vmeas = 2.5
Vref = 5
Cref = 2pF
Rref = 10000
|   typ   min   max
C_comp   5.008pF   4.673pF   5.008pF
|  Where Nom  PVT is Nominal Process, 5.0V,   27C
|   Fast PVT is Strong Process,  5.5,   -40C
|   Slow PVT is Weak Process,   4.5V,   150C
[Voltage Range]   5   4.5   5.5
|Junction Temperature
[Temperature Range]   27   150   -40
[Pullup Reference]   5   4.5   5.5
[Pulldown Reference]   0   -0   0
[Power Clamp Reference]   5   4.5   5.5
[GND Clamp Reference]   0   0   0
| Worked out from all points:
|   slope of the pulldown table from 0 to 0.75 V, typ, clamps not added: 165 ohm
|   GND clamp passes 1 mA (typ) near -0.63 V on its own axis
|   falling waveform, V_fixture 5V, R_fixture 10000Ohm: 20-80 % time 15.2ns typ, 16.1ns min, 14.6ns max; typ from 5 V to 0.083 V
|   rising waveform, V_fixture 5V, R_fixture 10000Ohm: 20-80 % time 79.5ns typ, 83ns min, 76.6ns max; typ from 0.083 V to 5 V
[Pulldown]
|   Voltage   I(typ)   I(min)   I(max)
-3V       -362.7uA   -227.6uA   -475.8uA
-1.185V   -734.3uA   -383.9uA   -1.054mA
-1.009V   -1.022mA   -473uA     -1.716mA
-899mV    -1.428mA   -567.9uA   -2.915mA
-822mV    -1.969mA   -670.3uA   -4.619mA
-701mV    -3.563mA   -943.5uA   -4.907mA
-459mV    -2.81mA    -1.979mA   -3.509mA
2.533V    14.51mA    11mA       18.49mA
3.611V    19.62mA    14.38mA    25.43mA
4.381V    22.21mA    15.57mA    29.59mA
5.261V    23.06mA    15.92mA    31.62mA
8V        23.57mA    16.39mA    32.29mA
[GND Clamp]
|   Voltage   I(typ)   I(min)   I(max)
-3V       -1.934A    -2.032A    -1.89A
-1.537V   -616.6mA   -743.7mA   -555.6mA
-1.207V   -333.3mA   -464.4mA   -269.5mA
-1.152V   -287.9mA   -419.1mA   -224.1mA
-987mV    -157.7mA   -286.9mA   -97.92mA
-877mV    -80.74mA   -203.3mA   -33.17mA
-789mV    -31.63mA   -140.9mA   -10.64mA
-635mV    -1.104mA   -49.54mA   -1.188mA
-558mV    -182.9uA   -19.06mA   -216.1uA
-459mV    -34.02uA   -2.535mA   -39.29uA
-239mV    -21.75uA   -25.32uA   -28.41uA
8V        0A         0A         0A
[POWER Clamp]
|   Voltage   I(typ)   I(min)   I(max)
-3V       12.5uA     11.46uA    14.89uA
-2.989V   12.4uA     11.37uA    14.79uA
-19mV     30.5nA     33.89nA    47.62nA
3mV       0A         0A         0A
8V        0A         0A         0A
[Ramp]
R_load = 10000
|   typ   min   max
dV/dt_r   2.94994/7.94528e-08   2.64307/8.29471e-08   3.25547/7.66162e-08
dV/dt_f   2.94994/1.52184e-08   2.64307/1.60506e-08   3.25547/1.46114e-08
[Falling Waveform]
V_fixture = 5V
V_fixture_min = 4.5V
V_fixture_max = 5.5V
R_fixture = 10000Ohm
C_fixture = 0F
|   Time   V(typ)   V(min)   V(max)
0s        5V         4.5V       5.5V
16.19ns   4.998V     4.496V     5.473V
18.53ns   4.972V     4.471V     5.302V
21.6ns    4.793V     4.342V     4.845V
29.44ns   3.612V     3.457V     3.202V
42.16ns   1.113V     1.342V     400.5mV
47.24ns   309.2mV    555.5mV    113.3mV
50.16ns   164.5mV    304.2mV    98.79mV
54.19ns   118.5mV    176.6mV    90.28mV
5us       83.43mV    94.78mV    74.22mV
[Rising Waveform]
V_fixture = 5V
V_fixture_min = 4.5V
V_fixture_max = 5.5V
R_fixture = 10000Ohm
C_fixture = 0F
|   Time   V(typ)   V(min)   V(max)
0s        83.43mV    94.78mV    74.22mV
71.79ns   228.2mV    226.4mV    250.2mV
83.4ns    642.3mV    471.3mV    816.4mV
109.5ns   2.035V     1.615V     2.392V
126.5ns   2.789V     2.305V     3.212V
155.1ns   3.68V      3.162V     4.173V
179.9ns   4.165V     3.639V     4.681V
234.1ns   4.701V     4.181V     5.222V
314.1ns   4.93V      4.421V     5.444V
5us       5V         4.5V       5.5V
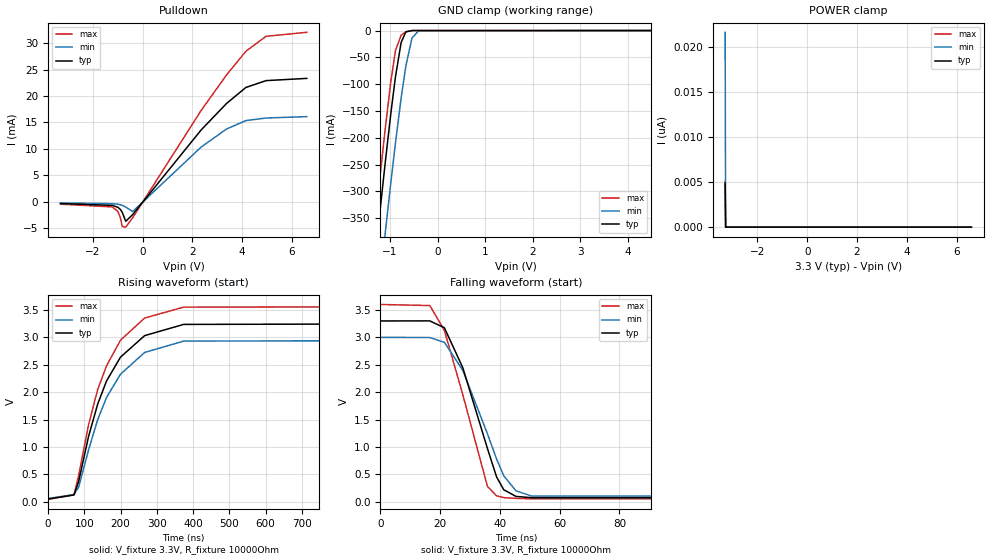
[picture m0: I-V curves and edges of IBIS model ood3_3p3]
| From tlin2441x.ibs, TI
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|   ood3_3p3 Model
[Model]   ood3_3p3
Model_type   Open_drain
Polarity   Non-Inverting
Vmeas = 1.65
Vref = 3.3
Cref = 2pF
Rref = 10000
|   typ   min   max
C_comp   5.292pF   5.008pF   5.317pF
|  Where Nom  PVT is Nominal Process, 3.3V,   27C
|   Fast PVT is Strong Process,  3.6,   -40C
|   Slow PVT is Weak Process,   3.0V,   150C
[Voltage Range]   3.3   3   3.6
|Junction Temperature
[Temperature Range]   27   150   -40
[Pullup Reference]   3.3   3   3.6
[Pulldown Reference]   0   0   0
[Power Clamp Reference]   3.3   3   3.6
[GND Clamp Reference]   0   0   0
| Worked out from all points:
|   slope of the pulldown table from 0 to 0.495 V, typ, clamps not added: 164 ohm
|   GND clamp passes 1 mA (typ) near -0.63 V on its own axis
|   falling waveform, V_fixture 3.3V, R_fixture 10000Ohm: 20-80 % time 11.1ns typ, 12.3ns min, 10.2ns max; typ from 3.3 V to 0.053 V
|   rising waveform, V_fixture 3.3V, R_fixture 10000Ohm: 20-80 % time 106ns typ, 110ns min, 102ns max; typ from 0.053 V to 3.3 V
[Pulldown]
|   Voltage   I(typ)   I(min)   I(max)
-3.3V     -352.4uA   -232.3uA   -465.3uA
-1.221V   -700uA     -371.1uA   -987.8uA
-993.3mV  -1.065mA   -484.4uA   -1.83mA
-894.3mV  -1.454mA   -573.7uA   -3.012mA
-815.1mV  -2.034mA   -682.4uA   -4.705mA
-676.5mV  -3.706mA   -1.023mA   -4.821mA
-399.3mV  -2.447mA   -1.87mA    -3.056mA
2.353V    13.57mA    10.33mA    17.26mA
3.373V    18.58mA    13.75mA    23.98mA
4.155V    21.63mA    15.36mA    28.49mA
4.966V    22.92mA    15.84mA    31.31mA
6.6V      23.34mA    16.1mA     32.06mA
[GND Clamp]
|   Voltage   I(typ)   I(min)   I(max)
-3.3V     -2.209A    -2.296A    -2.168A
-1.34V    -446.1mA   -576mA     -382.9mA
-1.33V    -437.6mA   -567.7mA   -374.4mA
-1.231V   -353.8mA   -484.8mA   -289.9mA
-1.102V   -247.9mA   -379.1mA   -184.6mA
-983.4mV  -155.5mA   -284.7mA   -96mA
-884.4mV  -86.04mA   -209.4mA   -37.19mA
-765.6mV  -22.36mA   -125.9mA   -8.744mA
-666.6mV  -2.548mA   -66.27mA   -2.296mA
-537.9mV  -105.6uA   -14.08mA   -119.4uA
-399.3mV  -2.05uA    -601.8uA   -1.172uA
6.6V      0A         0A         0A
[POWER Clamp]
|   Voltage   I(typ)   I(min)   I(max)
-3.3V     4.855nA    21.58nA    5.058nA
-3.28V    0A         0A         0A
-3.27V    0A         0A         0A
6.6V      0A         0A         0A
[Ramp]
R_load = 10000
|   typ   min   max
dV/dt_r   1.94827/1.05826e-07   1.7634/1.09483e-07   2.13221/1.01808e-07
dV/dt_f   1.94827/1.11044e-08   1.7634/1.23457e-08   2.13221/1.02311e-08
[Falling Waveform]
V_fixture = 3.3V
V_fixture_min = 3V
V_fixture_max = 3.6V
R_fixture = 10000Ohm
C_fixture = 0F
|   Time   V(typ)   V(min)   V(max)
0s        3.3V       3V         3.6V
16.51ns   3.301V     2.998V     3.581V
21.39ns   3.176V     2.909V     3.129V
27.56ns   2.447V     2.4V       1.956V
35.81ns   973.7mV    1.242V     282.4mV
38.89ns   453mV      780.3mV    109mV
41.28ns   220.9mV    474.9mV    77.18mV
45.36ns   99.95mV    202.1mV    63.16mV
50.57ns   75.83mV    106.2mV    55.24mV
5us       52.88mV    60.86mV    46.31mV
[Rising Waveform]
V_fixture = 3.3V
V_fixture_min = 3V
V_fixture_max = 3.6V
R_fixture = 10000Ohm
C_fixture = 0F
|   Time   V(typ)   V(min)   V(max)
0s        52.88mV    60.86mV    46.31mV
71.08ns   125.7mV    134mV      128.6mV
84.13ns   371.9mV    268.1mV    482.6mV
111.5ns   1.194V     948.1mV    1.408V
136.7ns   1.785V     1.501V     2.051V
161.1ns   2.206V     1.906V     2.481V
199.6ns   2.64V      2.329V     2.95V
266.1ns   3.032V     2.725V     3.353V
373.7ns   3.237V     2.932V     3.552V
5us       3.3V       3V         3.6V
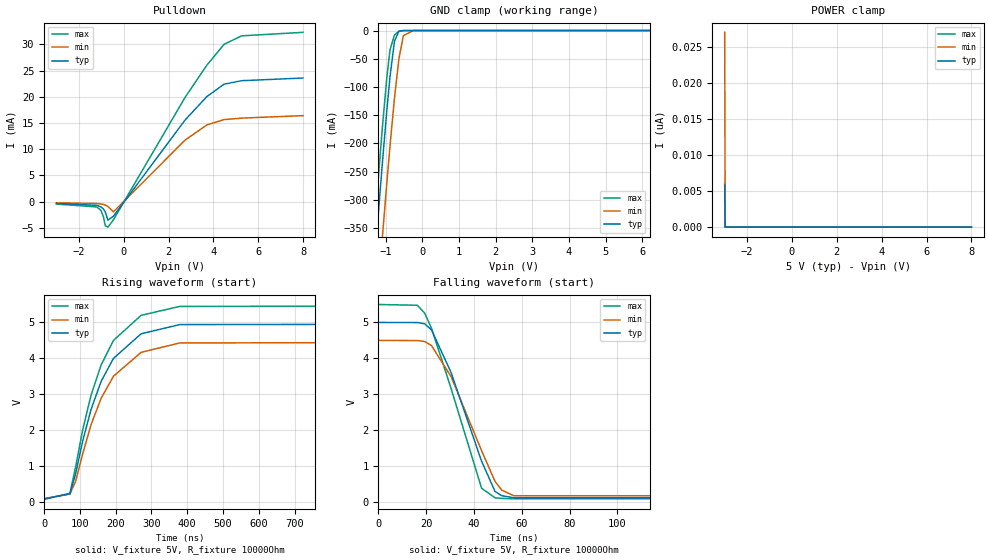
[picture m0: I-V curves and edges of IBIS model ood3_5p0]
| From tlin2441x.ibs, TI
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|   ood3_5p0 Model
[Model]   ood3_5p0
Model_type   Open_drain
Polarity   Non-Inverting
Vmeas = 2.5
Vref = 5
Cref = 2pF
Rref = 10000
|   typ   min   max
C_comp   5.008pF   4.673pF   5.008pF
|  Where Nom  PVT is Nominal Process, 5.0V,   27C
|   Fast PVT is Strong Process,  5.5,   -40C
|   Slow PVT is Weak Process,   4.5V,   150C
[Voltage Range]   5   4.5   5.5
|Junction Temperature
[Temperature Range]   27   150   -40
[Pullup Reference]   5   4.5   5.5
[Pulldown Reference]   0   0   0
[Power Clamp Reference]   5   4.5   5.5
[GND Clamp Reference]   0   0   0
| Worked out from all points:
|   slope of the pulldown table from 0 to 0.75 V, typ, clamps not added: 165 ohm
|   GND clamp passes 1 mA (typ) near -0.63 V on its own axis
|   falling waveform, V_fixture 5V, R_fixture 10000Ohm: 20-80 % time 15.5ns typ, 16.5ns min, 14.8ns max; typ from 5 V to 0.08 V
|   rising waveform, V_fixture 5V, R_fixture 10000Ohm: 20-80 % time 101ns typ, 104ns min, 97.2ns max; typ from 0.08 V to 5 V
[Pulldown]
|   Voltage   I(typ)   I(min)   I(max)
-3V       -362.3uA   -227uA     -475.3uA
-1.196V   -723.7uA   -380uA     -1.034mA
-1.009V   -1.023mA   -473.4uA   -1.721mA
-899mV    -1.429mA   -568.5uA   -2.923mA
-822mV    -1.967mA   -671.1uA   -4.605mA
-701mV    -3.545mA   -943.5uA   -4.888mA
-459mV    -2.81mA    -1.972mA   -3.509mA
2.742V    15.57mA    11.74mA    19.9mA
3.71V     20.03mA    14.62mA    26.02mA
4.48V     22.4mA     15.64mA    30.01mA
5.261V    23.06mA    15.92mA    31.62mA
8V        23.57mA    16.39mA    32.29mA
[GND Clamp]
|   Voltage   I(typ)   I(min)   I(max)
-3V       -1.935A    -2.033A    -1.891A
-1.537V   -617.1mA   -744.2mA   -556mA
-1.207V   -333.8mA   -465mA     -269.9mA
-1.141V   -279.3mA   -410.7mA   -215.6mA
-1.086V   -234.9mA   -366.1mA   -171.8mA
-965mV    -141.9mA   -270.4mA   -83.62mA
-877mV    -81.28mA   -203.9mA   -33.87mA
-756mV    -18.9mA    -119.6mA   -7.87mA
-635mV    -1.179mA   -50.15mA   -1.264mA
-514mV    -56.67uA   -9.047mA   -60.69uA
-239mV    0A         -8.055uA   0A
8V        0A         0A         0A
[POWER Clamp]
|   Voltage   I(typ)   I(min)   I(max)
-3V       5.832nA    27.02nA    6.176nA
-2.978V   0A         0A         0A
-2.967V   0A         0A         0A
8V        0A         0A         0A
[Ramp]
R_load = 10000
|   typ   min   max
dV/dt_r   2.9519/1.00903e-07   2.64508/1.03971e-07   3.25753/9.73677e-08
dV/dt_f   2.9519/1.54742e-08   2.64508/1.64438e-08   3.25753/1.47445e-08
[Falling Waveform]
V_fixture = 5V
V_fixture_min = 4.5V
V_fixture_max = 5.5V
R_fixture = 10000Ohm
C_fixture = 0F
|   Time   V(typ)   V(min)   V(max)
0s        5V         4.5V       5.5V
16.4ns    4.997V     4.495V     5.479V
19.44ns   4.962V     4.469V     5.258V
22.28ns   4.792V     4.356V     4.839V
30.47ns   3.605V     3.49V      3.161V
43.23ns   1.131V     1.424V     379.5mV
48.87ns   288.8mV    566.1mV    112.7mV
51.64ns   172.6mV    326.9mV    97.03mV
56.73ns   115.1mV    171.2mV    85.49mV
5us       80.16mV    91.38mV    70.78mV
[Rising Waveform]
V_fixture = 5V
V_fixture_min = 4.5V
V_fixture_max = 5.5V
R_fixture = 10000Ohm
C_fixture = 0F
|   Time   V(typ)   V(min)   V(max)
0s        80.16mV    91.38mV    70.78mV
72.4ns    224.5mV    218.5mV    240.2mV
88.43ns   791.9mV    578.1mV    981.8mV
108.3ns   1.71V      1.35V      2.025V
131.4ns   2.577V     2.155V     2.972V
159.6ns   3.36V      2.887V     3.82V
194ns     3.999V     3.503V     4.499V
271.1ns   4.684V     4.166V     5.198V
379ns     4.94V      4.429V     5.447V
5us       5V         4.5V       5.5V
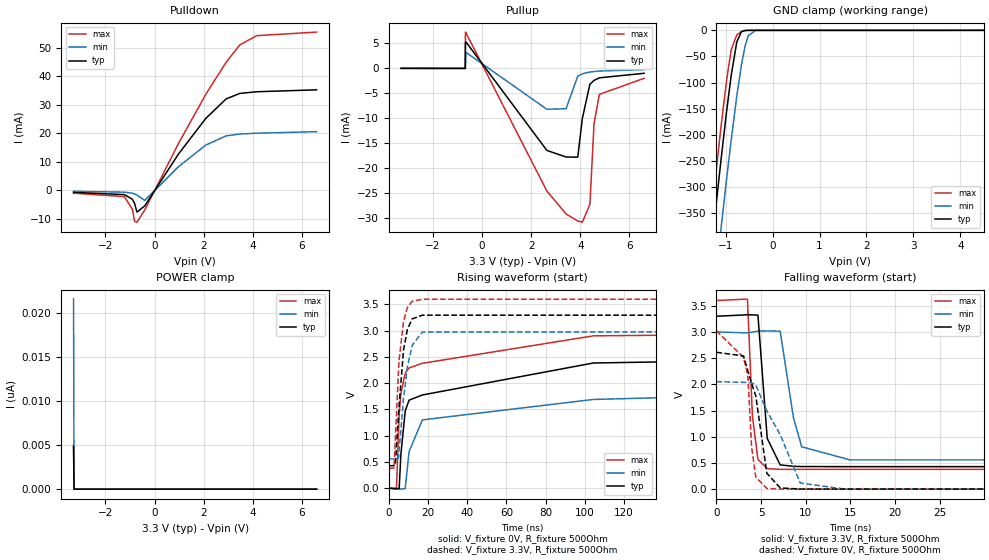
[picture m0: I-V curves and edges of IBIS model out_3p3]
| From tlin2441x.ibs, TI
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|   out_3p3 Model
[Model]   out_3p3
Model_type   3-state
Polarity   Non-Inverting
Vmeas = 1.65
Vref = 0
Cref = 2pF
Rref = 100000
|   typ   min   max
C_comp   5.172pF   4.738pF   5.220pF
|  Where Nom  PVT is Nominal Process, 3.3V,   27C
|   Fast PVT is Strong Process,  3.6,   -40C
|   Slow PVT is Weak Process,   3.0V,   150C
[Voltage Range]   3.3   3   3.6
|Junction Temperature
[Temperature Range]   27   150   -40
[Pullup Reference]   3.3   3   3.6
[Pulldown Reference]   0   0   -0
[Power Clamp Reference]   3.3   3   3.6
[GND Clamp Reference]   0   0   0
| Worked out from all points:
|   slope of the pulldown table from 0 to 0.495 V, typ, clamps not added: 74.8 ohm
|   slope of the pullup table from 0 to 0.495 V, typ, clamps not added: 130 ohm
|   GND clamp passes 1 mA (typ) near -0.63 V on its own axis
|   falling waveform, V_fixture 3.3V, R_fixture 500Ohm: 20-80 % time 743ps typ, 1.19ns min, 528ps max; typ from 3.3 V to 0.428 V
|   rising waveform, V_fixture 0V, R_fixture 500Ohm: 20-80 % time 46.7ns typ, 83.7ns min, 16ns max; typ from 0 V to 2.61 V
|   rising waveform, V_fixture 3.3V, R_fixture 500Ohm: 20-80 % time 3.64ns typ, 4.59ns min, 3.13ns max; typ from 0.428 V to 3.3 V
|   falling waveform, V_fixture 0V, R_fixture 500Ohm: 20-80 % time 1.57ns typ, 3.14ns min, 875ps max; typ from 2.61 V to 0 V
[Pulldown]
|   Voltage   I(typ)   I(min)   I(max)
-3.3V     -710.6uA   -342.7uA   -1.005mA
-1.231V   -1.497mA   -641.3uA   -2.2mA
-904.2mV  -3.121mA   -1.011mA   -6.613mA
-815.1mV  -4.579mA   -1.238mA   -10.83mA
-716.1mV  -7.626mA   -1.652mA   -11.16mA
-399.3mV  -5.433mA   -3.525mA   -6.874mA
976.8mV   12.75mA    8.313mA    16.45mA
2.086V    25.19mA    15.85mA    33.63mA
2.917V    32.04mA    19.09mA    44.89mA
3.472V    33.94mA    19.72mA    50.93mA
4.155V    34.53mA    20.01mA    54.18mA
6.6V      35.21mA    20.55mA    55.43mA
[GND Clamp]
|   Voltage   I(typ)   I(min)   I(max)
-3.3V     -2.209A    -2.296A    -2.168A
-1.33V    -437.6mA   -567.7mA   -374.4mA
-1.231V   -353.8mA   -484.8mA   -289.9mA
-1.102V   -247.9mA   -379.1mA   -184.6mA
-983.4mV  -155.5mA   -284.7mA   -96mA
-884.4mV  -86.04mA   -209.4mA   -37.19mA
-765.6mV  -22.36mA   -125.9mA   -8.744mA
-666.6mV  -2.548mA   -66.27mA   -2.296mA
-587.4mV  -367.2uA   -29.57mA   -432.9uA
-518.1mV  -63.14uA   -9.799mA   -68.36uA
-359.7mV  -525.4nA   -211.3uA   -181nA
6.6V      0A         0A         0A
[Pullup]
|   Voltage   I(typ)   I(min)   I(max)
-3.3V     13.19uA    10.31uA    18.33uA
-686.4mV  7.737uA    5.646uA    19.84uA
-676.5mV  5.236mA    8.243uA    7.283mA
-656.7mV  5.311mA    3.218mA    7.123mA
2.64V     -16.43mA   -8.181mA   -24.57mA
3.422V    -17.75mA   -8.071mA   -29.16mA
3.897V    -17.78mA   -1.551mA   -30.57mA
4.085V    -10.02mA   -1.073mA   -30.81mA
4.392V    -3.179mA   -724.4uA   -27.25mA
4.561V    -2.393mA   -617.4uA   -11.07mA
4.778V    -1.884mA   -519.8uA   -5.203mA
6.6V      -970.3uA   -243.8uA   -1.978mA
[POWER Clamp]
|   Voltage   I(typ)   I(min)   I(max)
-3.3V     4.855nA    21.58nA    5.058nA
-3.28V    0A         0A         0A
-3.27V    0A         0A         0A
6.6V      0A         0A         0A
[Ramp]
R_load = 500
|   typ   min   max
dV/dt_r   1.56746/4.57649e-08   1.23166/8.24173e-08   1.81407/1.60118e-08
dV/dt_f   1.72326/7.38834e-10   1.466/1.18514e-09   1.93436/5.27226e-10
[Falling Waveform]
V_fixture = 3.3V
V_fixture_min = 3V
V_fixture_max = 3.6V
R_fixture = 500Ohm
C_fixture = 0F
|   Time   V(typ)   V(min)   V(max)
0s        3.3V       3V         3.6V
3.475ns   3.328V     2.983V     3.628V
4.027ns   3.326V     2.998V     1.401V
4.648ns   3.321V     3.016V     569.3mV
5.689ns   969.1mV    3.021V     391.3mV
7.139ns   462.9mV    3.015V     378.2mV
8.623ns   436.2mV    1.362V     378.2mV
9.552ns   431.6mV    808mV      378.2mV
14.96ns   430mV      558.8mV    378.2mV
2.5us     427.9mV    556.7mV    376.1mV
[Rising Waveform]
V_fixture = 0V
V_fixture_min = 0V
V_fixture_max = 0V
R_fixture = 500Ohm
C_fixture = 0F
|   Time   V(typ)   V(min)   V(max)
0s        -472.1nV   861.7nV    122.5nV
3.861ns   -11.27mV   268.5uV    -19.2mV
5.247ns   -7.475mV   -16.64mV   1.389V
6.11ns    641mV      -15.38mV   1.795V
8.325ns   1.469V     -8.036mV   2.191V
10.28ns   1.675V     693.3mV    2.288V
17.09ns   1.774V     1.3V       2.377V
104.4ns   2.383V     1.689V     2.9V
409.8ns   2.567V     1.984V     2.999V
2.5us     2.612V     2.053V     3.023V
[Rising Waveform]
V_fixture = 3.3V
V_fixture_min = 3V
V_fixture_max = 3.6V
R_fixture = 500Ohm
C_fixture = 0F
|   Time   V(typ)   V(min)   V(max)
0s        427.9mV    556.7mV    376.1mV
2.564ns   427.2mV    557mV      382.6mV
3.277ns   437.2mV    557mV      917.2mV
4.908ns   1.406V     569.9mV    2.248V
5.262ns   1.598V     736.3mV    2.459V
7.476ns   2.633V     1.712V     3.177V
9.423ns   3.021V     2.301V     3.436V
11.89ns   3.223V     2.722V     3.558V
17.06ns   3.293V     2.971V     3.597V
2.5us     3.3V       3V         3.6V
[Falling Waveform]
|Gnd
V_fixture = 0V
V_fixture_min = 0V
V_fixture_max = 0V
R_fixture = 500Ohm
C_fixture = 0F
|   Time   V(typ)   V(min)   V(max)
0s        2.612V     2.053V     3.023V
3.037ns   2.543V     2.038V     2.513V
3.518ns   2.256V     2.036V     2.178V
3.945ns   2.014V     2.031V     796.8mV
4.406ns   1.782V     1.988V     231.3mV
5.644ns   304.5mV    1.492V     12.86mV
7.139ns   23.28mV    1.042V     1.904mV
9.38ns    2.646mV    118.4mV    1.902mV
14.35ns   2.102mV    1.841mV    1.899mV
2.5us     55.16nV    513.3nV    175.4nV
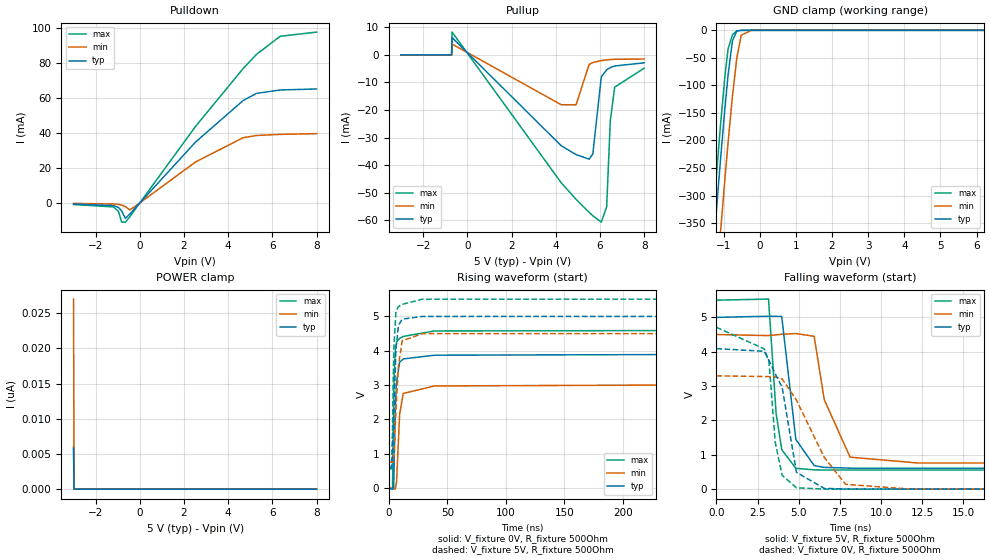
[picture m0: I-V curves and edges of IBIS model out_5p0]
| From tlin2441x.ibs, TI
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|   out_5p0 Model
[Model]   out_5p0
Model_type   3-state
Polarity   Non-Inverting
Vmeas = 2.5
Vref = 0
Cref = 2pF
Rref = 100000
|   typ   min   max
C_comp   5.148pF   4.827pF   5.148pF
|  Where Nom  PVT is Nominal Process, 5.0V,   27C
|   Fast PVT is Strong Process,  5.5,   -40C
|   Slow PVT is Weak Process,   4.5V,   150C
[Voltage Range]   5   4.5   5.5
|Junction Temperature
[Temperature Range]   27   150   -40
[Pullup Reference]   5   4.5   5.5
[Pulldown Reference]   0   0   0
[Power Clamp Reference]   5   4.5   5.5
[GND Clamp Reference]   0   0   0
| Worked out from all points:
|   slope of the pulldown table from 0 to 0.75 V, typ, clamps not added: 69.4 ohm
|   slope of the pullup table from 0 to 0.75 V, typ, clamps not added: 112 ohm
|   GND clamp passes 1 mA (typ) near -0.63 V on its own axis
|   falling waveform, V_fixture 5V, R_fixture 500Ohm: 20-80 % time 621ps typ, 945ps min, 466ps max; typ from 5 V to 0.607 V
|   rising waveform, V_fixture 0V, R_fixture 500Ohm: 20-80 % time 2.45ns typ, 4.19ns min, 1.6ns max; typ from 0 V to 4.09 V
|   rising waveform, V_fixture 5V, R_fixture 500Ohm: 20-80 % time 2.6ns typ, 3.75ns min, 1.71ns max; typ from 0.607 V to 5 V
|   falling waveform, V_fixture 0V, R_fixture 500Ohm: 20-80 % time 969ps typ, 1.96ns min, 535ps max; typ from 4.09 V to 0 V
[Pulldown]
|   Voltage   I(typ)   I(min)   I(max)
-3V       -832.4uA   -451.9uA   -1.098mA
-1.196V   -1.721mA   -786uA     -2.472mA
-965mV    -2.776mA   -1.053mA   -5.016mA
-822mV    -4.799mA   -1.402mA   -11.13mA
-657mV    -8.988mA   -2.3mA     -11.21mA
-459mV    -6.686mA   -4.137mA   -8.216mA
-239mV    -3.492mA   -2.402mA   -4.289mA
2.522V    34.66mA    23.27mA    43.61mA
4.678V    58.43mA    37.15mA    76.75mA
5.283V    62.52mA    38.4mA     84.85mA
6.35V     64.45mA    39.05mA    95.18mA
8V        65.05mA    39.46mA    97.58mA
[GND Clamp]
|   Voltage   I(typ)   I(min)   I(max)
-3V       -1.935A    -2.033A    -1.891A
-1.537V   -617.1mA   -744.2mA   -556mA
-1.207V   -333.8mA   -465mA     -269.9mA
-1.141V   -279.3mA   -410.7mA   -215.6mA
-1.086V   -234.9mA   -366.1mA   -171.8mA
-965mV    -141.9mA   -270.4mA   -83.62mA
-877mV    -81.28mA   -203.9mA   -33.87mA
-756mV    -18.9mA    -119.6mA   -7.87mA
-635mV    -1.179mA   -50.15mA   -1.264mA
-514mV    -56.67uA   -9.047mA   -60.69uA
-239mV    0A         -8.055uA   0A
8V        0A         0A         0A
[Pullup]
|   Voltage   I(typ)   I(min)   I(max)
-3V       15.99uA    12.27uA    22.57uA
-712mV    10.63uA    8.099uA    15.37uA
-690mV    6.319mA    3.954mA    8.306mA
4.249V    -32.99mA   -18.08mA   -46.45mA
4.92V     -36.19mA   -18.12mA   -52.45mA
5.514V    -37.87mA   -3.429mA   -57.2mA
5.679V    -35.97mA   -2.773mA   -58.41mA
6.064V    -7.943mA   -2.034mA   -60.76mA
6.306V    -5.383mA   -1.798mA   -55.12mA
6.471V    -4.584mA   -1.683mA   -23.8mA
6.669V    -4.009mA   -1.576mA   -11.69mA
8V        -2.857mA   -1.47mA    -4.832mA
[POWER Clamp]
|   Voltage   I(typ)   I(min)   I(max)
-3V       5.832nA    27.02nA    6.176nA
-2.978V   0A         0A         0A
-2.967V   0A         0A         0A
8V        0A         0A         0A
[Ramp]
R_load = 500
|   typ   min   max
dV/dt_r   2.45339/2.44927e-09   1.97797/4.18457e-09   2.82608/1.59967e-09
dV/dt_f   2.63553/6.19369e-10   2.24452/9.41152e-10   2.96761/4.64191e-10
[Falling Waveform]
V_fixture = 5V
V_fixture_min = 4.5V
V_fixture_max = 5.5V
R_fixture = 500Ohm
C_fixture = 0F
|   Time   V(typ)   V(min)   V(max)
0s        5V         4.5V       5.5V
3.166ns   5.032V     4.469V     5.532V
3.624ns   5.031V     4.491V     2.214V
3.966ns   5.027V     4.507V     1.153V
4.824ns   1.447V     4.528V     606.7mV
5.937ns   685.1mV    4.448V     562mV
6.549ns   634mV      2.604V     556.7mV
8.117ns   611.5mV    931.4mV    556.7mV
12.22ns   610.8mV    762.1mV    556.7mV
2.5us     607.5mV    759.1mV    554mV
[Rising Waveform]
V_fixture = 0V
V_fixture_min = 0V
V_fixture_max = 0V
R_fixture = 500Ohm
C_fixture = 0F
|   Time   V(typ)   V(min)   V(max)
0s        326.4nV    548.3nV    156.7nV
3.092ns   -27.33mV   355.1uV    -17.67mV
4.115ns   8.159mV    -16.34mV   2.705V
4.529ns   831.6mV    -22.77mV   3.32V
5.581ns   2.394V     -14.77mV   4.059V
6.549ns   3.087V     183mV      4.253V
9.179ns   3.663V     2.148V     4.357V
12.22ns   3.759V     2.755V     4.414V
39ns      3.868V     2.974V     4.573V
2.5us     4.089V     3.297V     4.71V
[Rising Waveform]
V_fixture = 5V
V_fixture_min = 4.5V
V_fixture_max = 5.5V
R_fixture = 500Ohm
C_fixture = 0F
|   Time   V(typ)   V(min)   V(max)
0s        607.5mV    759.1mV    554mV
2.154ns   604.6mV    759.1mV    564.8mV
3.082ns   976.3mV    759.1mV    1.663V
3.696ns   1.585V     759mV      3.192V
4.284ns   2.27V      980.4mV    4.115V
6.03ns    4.037V     2.276V     5.128V
8.117ns   4.729V     3.554V     5.28V
11.29ns   4.916V     4.284V     5.345V
28.57ns   4.995V     4.494V     5.497V
2.5us     5V         4.5V       5.5V
[Falling Waveform]
|Gnd
V_fixture = 0V
V_fixture_min = 0V
V_fixture_max = 0V
R_fixture = 500Ohm
C_fixture = 0F
|   Time   V(typ)   V(min)   V(max)
0s        4.089V     3.297V     4.71V
2.911ns   4.012V     3.278V     4.081V
3.195ns   3.744V     3.276V     3.7V
3.572ns   3.356V     3.27V      1.367V
3.991ns   2.969V     3.207V     404.1mV
4.861ns   489.1mV    2.592V     40.1mV
6.549ns   21.85mV    922.4mV    2.358mV
7.85ns    5.177mV    140.1mV    2.357mV
11.74ns   2.814mV    3.156mV    2.353mV
2.5us     357.7nV    -74.56nV   156.7nV
